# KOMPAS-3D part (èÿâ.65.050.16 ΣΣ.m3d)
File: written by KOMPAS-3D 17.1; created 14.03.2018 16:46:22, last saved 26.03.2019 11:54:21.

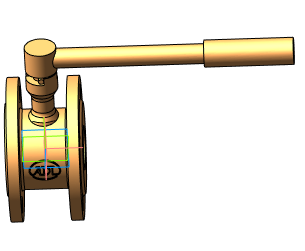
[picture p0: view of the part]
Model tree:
1. Операция без истории:2  (labels: Сталь 20  ГОСТ 1050-2013)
